VERSION 5.7 ;
  NOWIREEXTENSIONATPIN ON ;
  DIVIDERCHAR "/" ;
  BUSBITCHARS "[]" ;
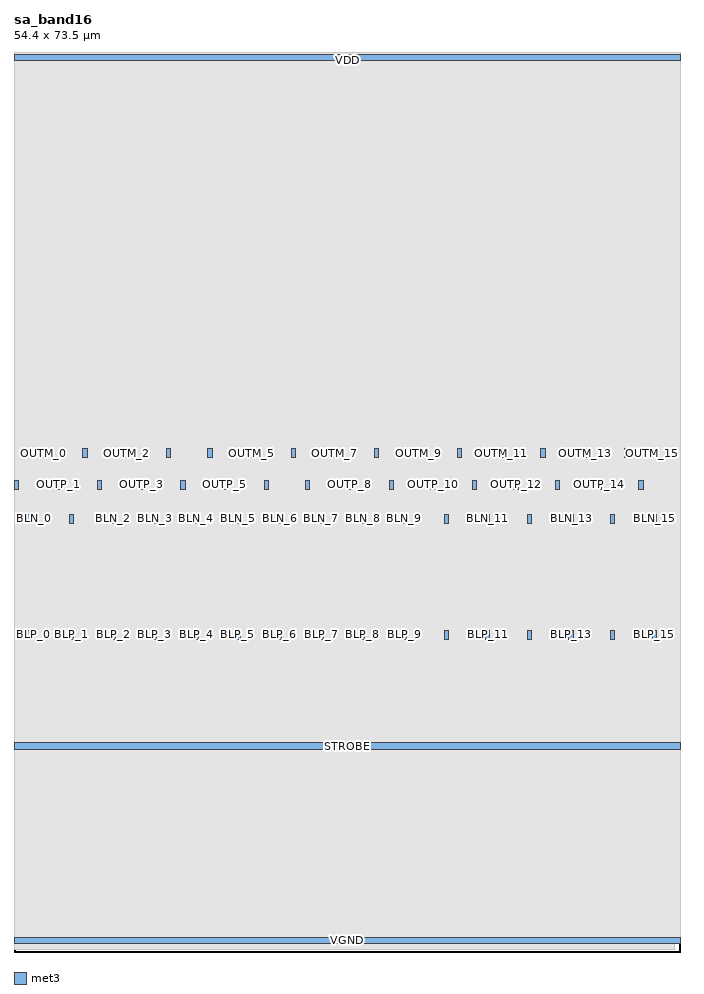
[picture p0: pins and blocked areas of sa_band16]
MACRO sa_band16
  CLASS BLOCK ;
  FOREIGN sa_band16 ;
  ORIGIN 0.000 0.500 ;
  SIZE 54.400 BY 73.500 ;
  PIN BLP_0
    ANTENNAGATEAREA 16.000000 ;
    PORT
      LAYER met3 ;
        RECT 1.120 25.030 1.460 25.770 ;
    END
  END BLP_0
  PIN BLN_0
    ANTENNAGATEAREA 16.000000 ;
    PORT
      LAYER met3 ;
        RECT 1.120 34.530 1.460 35.270 ;
    END
  END BLN_0
  PIN OUTP_0
    ANTENNAGATEAREA 12.000000 ;
    ANTENNADIFFAREA 3.723600 ;
    PORT
      LAYER met3 ;
        RECT 0.030 37.280 0.370 38.020 ;
    END
  END OUTP_0
  PIN OUTM_0
    ANTENNAGATEAREA 12.000000 ;
    ANTENNADIFFAREA 3.723600 ;
    PORT
      LAYER met3 ;
        RECT 2.230 39.880 2.570 40.620 ;
    END
  END OUTM_0
  PIN BLP_1
    ANTENNAGATEAREA 16.000000 ;
    PORT
      LAYER met3 ;
        RECT 4.520 25.030 4.860 25.770 ;
    END
  END BLP_1
  PIN BLN_1
    ANTENNAGATEAREA 16.000000 ;
    PORT
      LAYER met3 ;
        RECT 4.520 34.530 4.860 35.270 ;
    END
  END BLN_1
  PIN OUTP_1
    ANTENNAGATEAREA 12.000000 ;
    ANTENNADIFFAREA 3.723600 ;
    PORT
      LAYER met3 ;
        RECT 3.430 37.280 3.770 38.020 ;
    END
  END OUTP_1
  PIN OUTM_1
    ANTENNAGATEAREA 12.000000 ;
    ANTENNADIFFAREA 3.723600 ;
    PORT
      LAYER met3 ;
        RECT 5.630 39.880 5.970 40.620 ;
    END
  END OUTM_1
  PIN BLP_2
    ANTENNAGATEAREA 16.000000 ;
    PORT
      LAYER met3 ;
        RECT 7.920 25.030 8.260 25.770 ;
    END
  END BLP_2
  PIN BLN_2
    ANTENNAGATEAREA 16.000000 ;
    PORT
      LAYER met3 ;
        RECT 7.920 34.530 8.260 35.270 ;
    END
  END BLN_2
  PIN OUTP_2
    ANTENNAGATEAREA 12.000000 ;
    ANTENNADIFFAREA 3.723600 ;
    PORT
      LAYER met3 ;
        RECT 6.830 37.280 7.170 38.020 ;
    END
  END OUTP_2
  PIN OUTM_2
    ANTENNAGATEAREA 12.000000 ;
    ANTENNADIFFAREA 3.723600 ;
    PORT
      LAYER met3 ;
        RECT 9.030 39.880 9.370 40.620 ;
    END
  END OUTM_2
  PIN BLP_3
    ANTENNAGATEAREA 16.000000 ;
    PORT
      LAYER met3 ;
        RECT 11.320 25.030 11.660 25.770 ;
    END
  END BLP_3
  PIN BLN_3
    ANTENNAGATEAREA 16.000000 ;
    PORT
      LAYER met3 ;
        RECT 11.320 34.530 11.660 35.270 ;
    END
  END BLN_3
  PIN OUTP_3
    ANTENNAGATEAREA 12.000000 ;
    ANTENNADIFFAREA 3.723600 ;
    PORT
      LAYER met3 ;
        RECT 10.230 37.280 10.570 38.020 ;
    END
  END OUTP_3
  PIN OUTM_3
    ANTENNAGATEAREA 12.000000 ;
    ANTENNADIFFAREA 3.723600 ;
    PORT
      LAYER met3 ;
        RECT 12.430 39.880 12.770 40.620 ;
    END
  END OUTM_3
  PIN BLP_4
    ANTENNAGATEAREA 16.000000 ;
    PORT
      LAYER met3 ;
        RECT 14.720 25.030 15.060 25.770 ;
    END
  END BLP_4
  PIN BLN_4
    ANTENNAGATEAREA 16.000000 ;
    PORT
      LAYER met3 ;
        RECT 14.720 34.530 15.060 35.270 ;
    END
  END BLN_4
  PIN OUTP_4
    ANTENNAGATEAREA 12.000000 ;
    ANTENNADIFFAREA 3.723600 ;
    PORT
      LAYER met3 ;
        RECT 13.630 37.280 13.970 38.020 ;
    END
  END OUTP_4
  PIN OUTM_4
    ANTENNAGATEAREA 12.000000 ;
    ANTENNADIFFAREA 3.723600 ;
    PORT
      LAYER met3 ;
        RECT 15.830 39.880 16.170 40.620 ;
    END
  END OUTM_4
  PIN BLP_5
    ANTENNAGATEAREA 16.000000 ;
    PORT
      LAYER met3 ;
        RECT 18.120 25.030 18.460 25.770 ;
    END
  END BLP_5
  PIN BLN_5
    ANTENNAGATEAREA 16.000000 ;
    PORT
      LAYER met3 ;
        RECT 18.120 34.530 18.460 35.270 ;
    END
  END BLN_5
  PIN OUTP_5
    ANTENNAGATEAREA 12.000000 ;
    ANTENNADIFFAREA 3.723600 ;
    PORT
      LAYER met3 ;
        RECT 17.030 37.280 17.370 38.020 ;
    END
  END OUTP_5
  PIN OUTM_5
    ANTENNAGATEAREA 12.000000 ;
    ANTENNADIFFAREA 3.723600 ;
    PORT
      LAYER met3 ;
        RECT 19.230 39.880 19.570 40.620 ;
    END
  END OUTM_5
  PIN BLP_6
    ANTENNAGATEAREA 16.000000 ;
    PORT
      LAYER met3 ;
        RECT 21.520 25.030 21.860 25.770 ;
    END
  END BLP_6
  PIN BLN_6
    ANTENNAGATEAREA 16.000000 ;
    PORT
      LAYER met3 ;
        RECT 21.520 34.530 21.860 35.270 ;
    END
  END BLN_6
  PIN OUTP_6
    ANTENNAGATEAREA 12.000000 ;
    ANTENNADIFFAREA 3.723600 ;
    PORT
      LAYER met3 ;
        RECT 20.430 37.280 20.770 38.020 ;
    END
  END OUTP_6
  PIN OUTM_6
    ANTENNAGATEAREA 12.000000 ;
    ANTENNADIFFAREA 3.723600 ;
    PORT
      LAYER met3 ;
        RECT 22.630 39.880 22.970 40.620 ;
    END
  END OUTM_6
  PIN BLP_7
    ANTENNAGATEAREA 16.000000 ;
    PORT
      LAYER met3 ;
        RECT 24.920 25.030 25.260 25.770 ;
    END
  END BLP_7
  PIN BLN_7
    ANTENNAGATEAREA 16.000000 ;
    PORT
      LAYER met3 ;
        RECT 24.920 34.530 25.260 35.270 ;
    END
  END BLN_7
  PIN OUTP_7
    ANTENNAGATEAREA 12.000000 ;
    ANTENNADIFFAREA 3.723600 ;
    PORT
      LAYER met3 ;
        RECT 23.830 37.280 24.170 38.020 ;
    END
  END OUTP_7
  PIN OUTM_7
    ANTENNAGATEAREA 12.000000 ;
    ANTENNADIFFAREA 3.723600 ;
    PORT
      LAYER met3 ;
        RECT 26.030 39.880 26.370 40.620 ;
    END
  END OUTM_7
  PIN BLP_8
    ANTENNAGATEAREA 16.000000 ;
    PORT
      LAYER met3 ;
        RECT 28.320 25.030 28.660 25.770 ;
    END
  END BLP_8
  PIN BLN_8
    ANTENNAGATEAREA 16.000000 ;
    PORT
      LAYER met3 ;
        RECT 28.320 34.530 28.660 35.270 ;
    END
  END BLN_8
  PIN OUTP_8
    ANTENNAGATEAREA 12.000000 ;
    ANTENNADIFFAREA 3.723600 ;
    PORT
      LAYER met3 ;
        RECT 27.230 37.280 27.570 38.020 ;
    END
  END OUTP_8
  PIN OUTM_8
    ANTENNAGATEAREA 12.000000 ;
    ANTENNADIFFAREA 3.723600 ;
    PORT
      LAYER met3 ;
        RECT 29.430 39.880 29.770 40.620 ;
    END
  END OUTM_8
  PIN BLP_9
    ANTENNAGATEAREA 16.000000 ;
    PORT
      LAYER met3 ;
        RECT 31.720 25.030 32.060 25.770 ;
    END
  END BLP_9
  PIN BLN_9
    ANTENNAGATEAREA 16.000000 ;
    PORT
      LAYER met3 ;
        RECT 31.720 34.530 32.060 35.270 ;
    END
  END BLN_9
  PIN OUTP_9
    ANTENNAGATEAREA 12.000000 ;
    ANTENNADIFFAREA 3.723600 ;
    PORT
      LAYER met3 ;
        RECT 30.630 37.280 30.970 38.020 ;
    END
  END OUTP_9
  PIN OUTM_9
    ANTENNAGATEAREA 12.000000 ;
    ANTENNADIFFAREA 3.723600 ;
    PORT
      LAYER met3 ;
        RECT 32.830 39.880 33.170 40.620 ;
    END
  END OUTM_9
  PIN BLP_10
    ANTENNAGATEAREA 16.000000 ;
    PORT
      LAYER met3 ;
        RECT 35.120 25.030 35.460 25.770 ;
    END
  END BLP_10
  PIN BLN_10
    ANTENNAGATEAREA 16.000000 ;
    PORT
      LAYER met3 ;
        RECT 35.120 34.530 35.460 35.270 ;
    END
  END BLN_10
  PIN OUTP_10
    ANTENNAGATEAREA 12.000000 ;
    ANTENNADIFFAREA 3.723600 ;
    PORT
      LAYER met3 ;
        RECT 34.030 37.280 34.370 38.020 ;
    END
  END OUTP_10
  PIN OUTM_10
    ANTENNAGATEAREA 12.000000 ;
    ANTENNADIFFAREA 3.723600 ;
    PORT
      LAYER met3 ;
        RECT 36.230 39.880 36.570 40.620 ;
    END
  END OUTM_10
  PIN BLP_11
    ANTENNAGATEAREA 16.000000 ;
    PORT
      LAYER met3 ;
        RECT 38.520 25.030 38.860 25.770 ;
    END
  END BLP_11
  PIN BLN_11
    ANTENNAGATEAREA 16.000000 ;
    PORT
      LAYER met3 ;
        RECT 38.520 34.530 38.860 35.270 ;
    END
  END BLN_11
  PIN OUTP_11
    ANTENNAGATEAREA 12.000000 ;
    ANTENNADIFFAREA 3.723600 ;
    PORT
      LAYER met3 ;
        RECT 37.430 37.280 37.770 38.020 ;
    END
  END OUTP_11
  PIN OUTM_11
    ANTENNAGATEAREA 12.000000 ;
    ANTENNADIFFAREA 3.723600 ;
    PORT
      LAYER met3 ;
        RECT 39.630 39.880 39.970 40.620 ;
    END
  END OUTM_11
  PIN BLP_12
    ANTENNAGATEAREA 16.000000 ;
    PORT
      LAYER met3 ;
        RECT 41.920 25.030 42.260 25.770 ;
    END
  END BLP_12
  PIN BLN_12
    ANTENNAGATEAREA 16.000000 ;
    PORT
      LAYER met3 ;
        RECT 41.920 34.530 42.260 35.270 ;
    END
  END BLN_12
  PIN OUTP_12
    ANTENNAGATEAREA 12.000000 ;
    ANTENNADIFFAREA 3.723600 ;
    PORT
      LAYER met3 ;
        RECT 40.830 37.280 41.170 38.020 ;
    END
  END OUTP_12
  PIN OUTM_12
    ANTENNAGATEAREA 12.000000 ;
    ANTENNADIFFAREA 3.723600 ;
    PORT
      LAYER met3 ;
        RECT 43.030 39.880 43.370 40.620 ;
    END
  END OUTM_12
  PIN BLP_13
    ANTENNAGATEAREA 16.000000 ;
    PORT
      LAYER met3 ;
        RECT 45.320 25.030 45.660 25.770 ;
    END
  END BLP_13
  PIN BLN_13
    ANTENNAGATEAREA 16.000000 ;
    PORT
      LAYER met3 ;
        RECT 45.320 34.530 45.660 35.270 ;
    END
  END BLN_13
  PIN OUTP_13
    ANTENNAGATEAREA 12.000000 ;
    ANTENNADIFFAREA 3.723600 ;
    PORT
      LAYER met3 ;
        RECT 44.230 37.280 44.570 38.020 ;
    END
  END OUTP_13
  PIN OUTM_13
    ANTENNAGATEAREA 12.000000 ;
    ANTENNADIFFAREA 3.723600 ;
    PORT
      LAYER met3 ;
        RECT 46.430 39.880 46.770 40.620 ;
    END
  END OUTM_13
  PIN BLP_14
    ANTENNAGATEAREA 16.000000 ;
    PORT
      LAYER met3 ;
        RECT 48.720 25.030 49.060 25.770 ;
    END
  END BLP_14
  PIN BLN_14
    ANTENNAGATEAREA 16.000000 ;
    PORT
      LAYER met3 ;
        RECT 48.720 34.530 49.060 35.270 ;
    END
  END BLN_14
  PIN OUTP_14
    ANTENNAGATEAREA 12.000000 ;
    ANTENNADIFFAREA 3.723600 ;
    PORT
      LAYER met3 ;
        RECT 47.630 37.280 47.970 38.020 ;
    END
  END OUTP_14
  PIN OUTM_14
    ANTENNAGATEAREA 12.000000 ;
    ANTENNADIFFAREA 3.723600 ;
    PORT
      LAYER met3 ;
        RECT 49.830 39.880 50.170 40.620 ;
    END
  END OUTM_14
  PIN BLP_15
    ANTENNAGATEAREA 16.000000 ;
    PORT
      LAYER met3 ;
        RECT 52.120 25.030 52.460 25.770 ;
    END
  END BLP_15
  PIN BLN_15
    ANTENNAGATEAREA 16.000000 ;
    PORT
      LAYER met3 ;
        RECT 52.120 34.530 52.460 35.270 ;
    END
  END BLN_15
  PIN OUTP_15
    ANTENNAGATEAREA 12.000000 ;
    ANTENNADIFFAREA 3.723600 ;
    PORT
      LAYER met3 ;
        RECT 51.030 37.280 51.370 38.020 ;
    END
  END OUTP_15
  PIN OUTM_15
    ANTENNAGATEAREA 12.000000 ;
    ANTENNADIFFAREA 3.723600 ;
    PORT
      LAYER met3 ;
        RECT 53.230 39.880 53.570 40.620 ;
    END
  END OUTM_15
  PIN STROBE
    ANTENNAGATEAREA 250.879990 ;
    PORT
      LAYER met3 ;
        RECT 0.000 16.000 54.400 16.600 ;
    END
  END STROBE
  PIN VDD
    USE POWER ;
    PORT
      LAYER met3 ;
        RECT 0.000 72.300 54.400 72.800 ;
    END
  END VDD
  PIN VGND
    USE GROUND ;
    PORT
      LAYER met3 ;
        RECT 0.000 0.200 54.400 0.700 ;
    END
  END VGND
  OBS
      LAYER nwell ;
        RECT 0.000 47.500 54.400 73.000 ;
      LAYER li1 ;
        RECT 0.060 -0.300 53.920 72.055 ;
      LAYER met1 ;
        RECT 0.000 0.200 54.400 72.160 ;
      LAYER met2 ;
        RECT 0.000 0.200 54.400 72.800 ;
  END
END sa_band16
END LIBRARY

